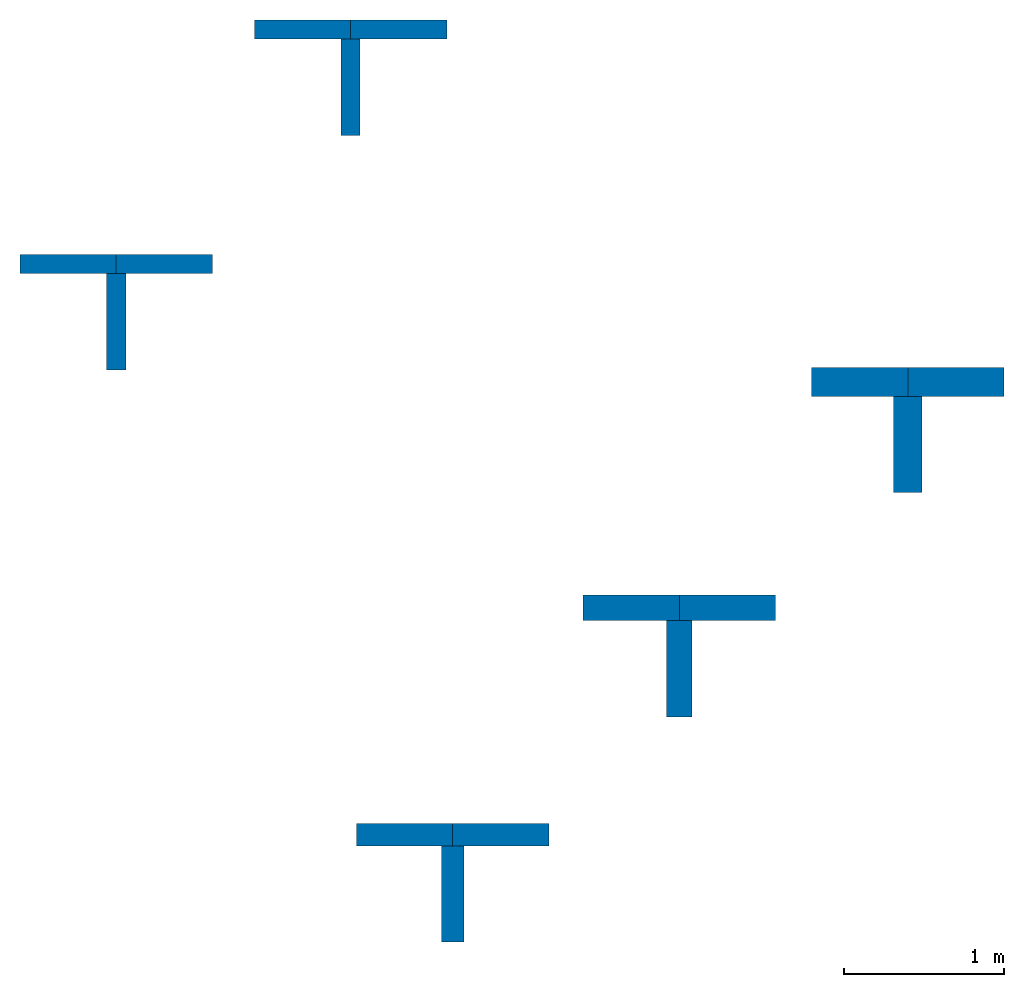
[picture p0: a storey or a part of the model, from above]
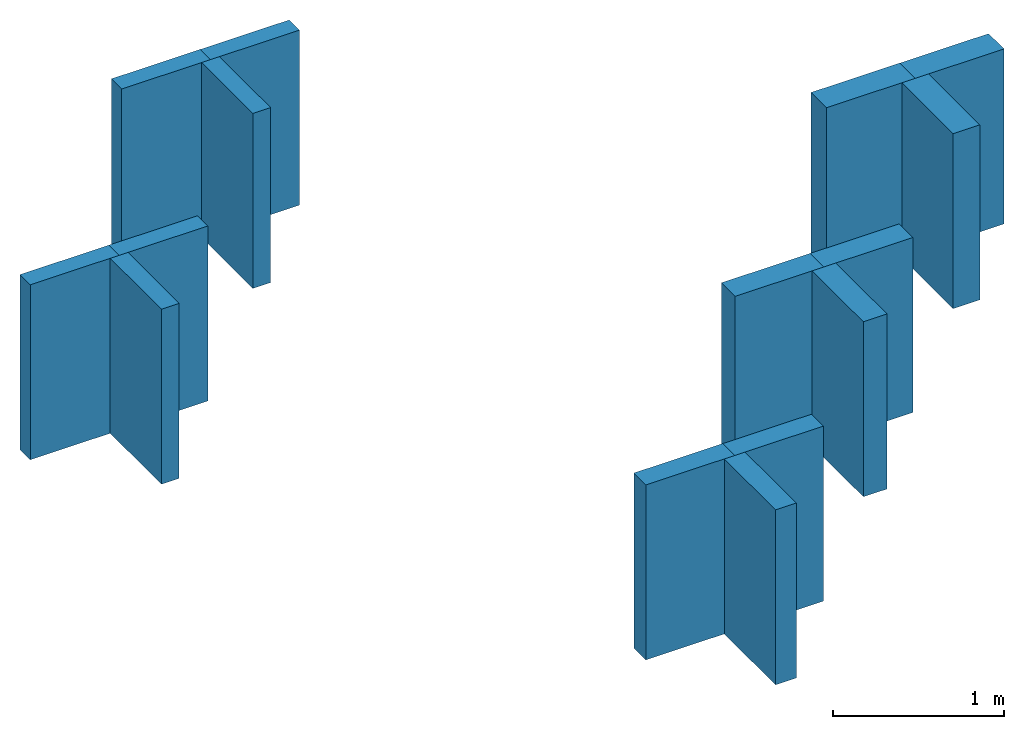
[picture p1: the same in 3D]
Properties of the parts of a building model (IFC2X3)

# File
Description: ViewDefinition [CoordinationView]
Time: 2023-01-18T13:19:16
Written by: The EXPRESS Data Manager Version 5.02.0100.07 : 28 Aug 2013
Made in: 21.1.70.21 - Exporter 21.1.70.21 - Alternate UI 21.1.70.21
Comment: STEP Physical File produced by: The EXPRESS Data Manager Version 5.02.0100.07 : 28 Aug 2013 * Module: EDMstepFileFactory/EDMstandAlone * Creation date: Wed Jan 18 13:19:16 2023 * Host: BIM-LT03 * Database: C:\Users\DONNEE~1\AppData\Local\Temp\6dfd9f73-01cb-4fe2-bb7c-203e315a706e\86299734-407f-49fc-b1f2-134ff55dd5cc\ifc * Database version: 5507 * Database creation date: Wed Jan 18 13:19:15 2023 * Schema: IFC2X3 * Model: DataRepository.ifc * Model creation date: Wed Jan 18 13:19:15 2023 * Header model: DataRepository.ifc_HeaderModel * Header model creation date: Wed Jan 18 13:19:15 2023 * EDMuser: sdai-user * EDMgroup: sdai-group * License ID and type: 5605 : Permanent license. Expiry date: * EDMstepFileFactory options: 020000

# IfcSite, Default
RefLatitude: 42, 24, 53, 508911; RefLongitude: -71, -15, -29, -58837; RefElevation: 0 mm
Pset_ProductRequirements - Category: Project Information

# IfcBuilding
Pset_BuildingCommon - NumberOfStoreys: 1
Pset_ProductRequirements - Category: Project Information

# IfcBuildingStorey: Level:NL_00_niveau, Begane grond
LongName: Begane grond; Elevation: 0 mm
Pset_AirSideSystemInformation - Name: Begane grond
Pset_ProductRequirements - Name: Begane grond; Category: Levels

# IfcWallStandardCase: Basic Wall:NLRS_21_WA_SmartCavity 031_100x600x1250mm (3)
In: Begane grond
Type - PredefinedType: STANDARD; Material: Knauf Insulation_Ecose® glaswol_TP 432KD 120 mm
Type - Pset_ElementShading - Roughness: 304.8 mm
Type - Pset_ManufacturerTypeInformation - Manufacturer: Knauf Insulation B.V.
Type - Pset_ProductRequirements - Category: Walls
Type - Pset_QuantityTakeOff - Reference: Basic Wall:NLRS_21_WA_SmartCavity 031_100x600x1250mm
Type - Pset_ReinforcementBarPitchOfWall - Description: SmartCavity 031 - 100mm; Reference: Basic Wall:NLRS_21_WA_SmartCavity 031_100x600x1250mm
Type - Pset_WallCommon - IsExternal: no; Reference: Basic Wall:NLRS_21_WA_SmartCavity 031_100x600x1250mm; ThermalTransmittance: 0.283333 kg/K/s3
Type - Pset_Wall Schedule SmartCavity031 LOD400 - Assembly Code: 21; Type Image: Raster image: SMARTCAVITY 031_Packshot_3.jpg; Model: SmartCavity 031 is een stevige met zwart glasvlies beklede glaswol spouwplaat met ECOSE® Technology; Manufacturer: Knauf Insulation B.V.; URL: www.knaufinsulation.nl www.knaufinsulation.nl www.knaufinsulation.nl; Description: SmartCavity 031 - 100mm; phone: +31(0)162-421245; email: customerservice.nl@knaufinsulation.com; product URL: https://www.knaufinsulation.nl/producten-van-knauf-insulation/SmartCavity-031; warmteweerstand: 3.2; NLRS_C_Code_Brandklasse: A1; warmtegeleidingscoëfficiënt: 0.031; kortstondige waterabsorptie: WS; langdurige waterabsorptie: WL(P); luchtstroomweerstand: AFr12; DoP nummer (Declaration of performance): G4220PPCPR; NLRS_C_content_creator: Knauf Insulation; NLRS_C_content_versie: V1.0; diktebereik: 30 - 260; diktetolerantie: T4; platen / pak: 5; pak (m2): 3.75; pakken / pallet: 20; pallet (m2): 75
Classification: 21 Buitenwanden (Uniformat)
Pset_WallCommon - IsExternal: yes; ExtendToStructure: no; LoadBearing: no
Pset_Wall Schedule SmartCavity031 LOD400 - Type: Basic Wall: NLRS_21_WA_SmartCavity 031_100x600x1250mm
Name (Basic Wall:NLRS_21_WA_SmartCavity 031_100x600x1250mm:...)
8517
8518
8519

# IfcWallStandardCase: Basic Wall:NLRS_21_WA_SmartCavity 031_120x600x1250mm (3)
In: Begane grond
Type - PredefinedType: STANDARD; Material: Knauf Insulation_Ecose® glaswol_TP 432KD 120 mm
Type - Pset_ElementShading - Roughness: 304.8 mm
Type - Pset_ManufacturerTypeInformation - Manufacturer: Knauf Insulation B.V.
Type - Pset_ProductRequirements - Category: Walls
Type - Pset_QuantityTakeOff - Reference: Basic Wall:NLRS_21_WA_SmartCavity 031_120x600x1250mm
Type - Pset_ReinforcementBarPitchOfWall - Description: SmartCavity 031 - 120mm; Reference: Basic Wall:NLRS_21_WA_SmartCavity 031_120x600x1250mm
Type - Pset_WallCommon - Reference: Basic Wall:NLRS_21_WA_SmartCavity 031_120x600x1250mm; ThermalTransmittance: 0.283333 kg/K/s3; IsExternal: no
Type - Pset_Wall Schedule SmartCavity031 LOD400 - Assembly Code: 21; Type Image: Raster image: SMARTCAVITY 031_Packshot_3.jpg; Model: SmartCavity 031 is een stevige met zwart glasvlies beklede glaswol spouwplaat met ECOSE® Technology; Manufacturer: Knauf Insulation B.V.; URL: www.knaufinsulation.nl www.knaufinsulation.nl www.knaufinsulation.nl; Description: SmartCavity 031 - 120mm; phone: +31(0)162-421245; email: customerservice.nl@knaufinsulation.com; product URL: https://www.knaufinsulation.nl/producten-van-knauf-insulation/SmartCavity-031; warmteweerstand: 3.85; NLRS_C_Code_Brandklasse: A1; warmtegeleidingscoëfficiënt: 0.031; kortstondige waterabsorptie: WS; langdurige waterabsorptie: WL(P); luchtstroomweerstand: AFr12; DoP nummer (Declaration of performance): G4220PPCPR; NLRS_C_content_creator: Knauf Insulation; NLRS_C_content_versie: V1.0; diktebereik: 30 - 260; diktetolerantie: T4; platen / pak: 4; pak (m2): 3; pakken / pallet: 20; pallet (m2): 60
Classification: 21 Buitenwanden (Uniformat)
Pset_WallCommon - IsExternal: yes; ExtendToStructure: no; LoadBearing: no
Pset_Wall Schedule SmartCavity031 LOD400 - Type: Basic Wall: NLRS_21_WA_SmartCavity 031_120x600x1250mm
Name (Basic Wall:NLRS_21_WA_SmartCavity 031_120x600x1250mm:...)
2447
2448
2449

# IfcWallStandardCase: Basic Wall:NLRS_21_WA_SmartCavity 031_140x600x1250mm (3)
In: Begane grond
Type - PredefinedType: STANDARD; Material: Knauf Insulation_Ecose® glaswol_TP 432KD 140 mm
Type - Pset_ElementShading - Roughness: 304.8 mm
Type - Pset_ManufacturerTypeInformation - Manufacturer: Knauf Insulation B.V.
Type - Pset_ProductRequirements - Category: Walls
Type - Pset_QuantityTakeOff - Reference: Basic Wall:NLRS_21_WA_SmartCavity 031_140x600x1250mm
Type - Pset_ReinforcementBarPitchOfWall - Description: SmartCavity 031 - 140mm; Reference: Basic Wall:NLRS_21_WA_SmartCavity 031_140x600x1250mm
Type - Pset_WallCommon - IsExternal: no; Reference: Basic Wall:NLRS_21_WA_SmartCavity 031_140x600x1250mm; ThermalTransmittance: 0.242857 kg/K/s3
Type - Pset_Wall Schedule SmartCavity031 LOD400 - platen / pak: 4; pak (m2): 3; Assembly Code: 21; Type Image: Raster image: SMARTCAVITY 031_Packshot_3.jpg; Model: SmartCavity 031 is een stevige met zwart glasvlies beklede glaswol spouwplaat met ECOSE® Technology; Manufacturer: Knauf Insulation B.V.; URL: www.knaufinsulation.nl www.knaufinsulation.nl www.knaufinsulation.nl; Description: SmartCavity 031 - 140mm; phone: +31(0)162-421245; email: customerservice.nl@knaufinsulation.com; product URL: https://www.knaufinsulation.nl/producten-van-knauf-insulation/SmartCavity-031; warmteweerstand: 4.5; NLRS_C_Code_Brandklasse: A1; warmtegeleidingscoëfficiënt: 0.031; kortstondige waterabsorptie: WS; langdurige waterabsorptie: WL(P); luchtstroomweerstand: AFr12; DoP nummer (Declaration of performance): G4220PPCPR; NLRS_C_content_creator: Knauf Insulation; NLRS_C_content_versie: V1.0; diktebereik: 30 - 260; diktetolerantie: T4; pakken / pallet: 16; pallet (m2): 48
Classification: 21 Buitenwanden (Uniformat)
Pset_WallCommon - IsExternal: yes; ExtendToStructure: no; LoadBearing: no
Pset_Wall Schedule SmartCavity031 LOD400 - Type: Basic Wall: NLRS_21_WA_SmartCavity 031_140x600x1250mm
Name (Basic Wall:NLRS_21_WA_SmartCavity 031_140x600x1250mm:...)
2450
2451
2452

# IfcWallStandardCase: Basic Wall:NLRS_21_WA_SmartCavity 031_160x600x1250mm (3)
In: Begane grond
Type - PredefinedType: STANDARD; Material: Knauf Insulation_Ecose® glaswol_TP 432KD 160 mm
Type - Pset_ElementShading - Roughness: 304.8 mm
Type - Pset_ManufacturerTypeInformation - Manufacturer: Knauf Insulation B.V.
Type - Pset_ProductRequirements - Category: Walls
Type - Pset_QuantityTakeOff - Reference: Basic Wall:NLRS_21_WA_SmartCavity 031_160x600x1250mm
Type - Pset_ReinforcementBarPitchOfWall - Description: SmartCavity 031 - 160mm; Reference: Basic Wall:NLRS_21_WA_SmartCavity 031_160x600x1250mm
Type - Pset_WallCommon - IsExternal: no; Reference: Basic Wall:NLRS_21_WA_SmartCavity 031_160x600x1250mm; ThermalTransmittance: 0.2125 kg/K/s3
Type - Pset_Wall Schedule SmartCavity031 LOD400 - Assembly Code: 21; Type Image: Raster image: SMARTCAVITY 031_Packshot_3.jpg; Model: SmartCavity 031 is een stevige met zwart glasvlies beklede glaswol spouwplaat met ECOSE® Technology; Manufacturer: Knauf Insulation B.V.; URL: www.knaufinsulation.nl www.knaufinsulation.nl www.knaufinsulation.nl; Description: SmartCavity 031 - 160mm; phone: +31(0)162-421245; email: customerservice.nl@knaufinsulation.com; product URL: https://www.knaufinsulation.nl/producten-van-knauf-insulation/SmartCavity-031; warmteweerstand: 5.15; NLRS_C_Code_Brandklasse: A1; warmtegeleidingscoëfficiënt: 0.031; kortstondige waterabsorptie: WS; langdurige waterabsorptie: WL(P); luchtstroomweerstand: AFr12; DoP nummer (Declaration of performance): G4220PPCPR; NLRS_C_content_creator: Knauf Insulation; NLRS_C_content_versie: V1.0; diktebereik: 30 - 260; diktetolerantie: T4; platen / pak: 3; pak (m2): 2.25; pakken / pallet: 20; pallet (m2): 45
Classification: 21 Buitenwanden (Uniformat)
Pset_WallCommon - IsExternal: yes; ExtendToStructure: no; LoadBearing: no
Pset_Wall Schedule SmartCavity031 LOD400 - Type: Basic Wall: NLRS_21_WA_SmartCavity 031_160x600x1250mm
Name (Basic Wall:NLRS_21_WA_SmartCavity 031_160x600x1250mm:...)
2453
2454
2455

# IfcWallStandardCase: Basic Wall:NLRS_21_WA_SmartCavity 031_180x600x1250mm (3)
In: Begane grond
Type - PredefinedType: STANDARD; Material: Knauf Insulation_Ecose® glaswol_TP 432KD 180 mm
Type - Pset_ElementShading - Roughness: 304.8 mm
Type - Pset_ManufacturerTypeInformation - Manufacturer: Knauf Insulation B.V.
Type - Pset_ProductRequirements - Category: Walls
Type - Pset_QuantityTakeOff - Reference: Basic Wall:NLRS_21_WA_SmartCavity 031_180x600x1250mm
Type - Pset_ReinforcementBarPitchOfWall - Description: SmartCavity 031 - 180mm; Reference: Basic Wall:NLRS_21_WA_SmartCavity 031_180x600x1250mm
Type - Pset_WallCommon - IsExternal: no; Reference: Basic Wall:NLRS_21_WA_SmartCavity 031_180x600x1250mm; ThermalTransmittance: 0.188889 kg/K/s3
Type - Pset_Wall Schedule SmartCavity031 LOD400 - platen / pak: 3; Assembly Code: 21; Type Image: Raster image: SMARTCAVITY 031_Packshot_3.jpg; Model: SmartCavity 031 is een stevige met zwart glasvlies beklede glaswol spouwplaat met ECOSE® Technology; Manufacturer: Knauf Insulation B.V.; URL: www.knaufinsulation.nl www.knaufinsulation.nl www.knaufinsulation.nl; Description: SmartCavity 031 - 180mm; phone: +31(0)162-421245; email: customerservice.nl@knaufinsulation.com; product URL: https://www.knaufinsulation.nl/producten-van-knauf-insulation/SmartCavity-031; warmteweerstand: 5.8; NLRS_C_Code_Brandklasse: A1; warmtegeleidingscoëfficiënt: 0.031; kortstondige waterabsorptie: WS; langdurige waterabsorptie: WL(P); luchtstroomweerstand: AFr12; DoP nummer (Declaration of performance): G4220PPCPR; NLRS_C_content_creator: Knauf Insulation; NLRS_C_content_versie: V1.0; diktebereik: 30 - 260; diktetolerantie: T4; pak (m2): 2.25; pakken / pallet: 16; pallet (m2): 36
Classification: 21 Buitenwanden (Uniformat)
Pset_WallCommon - IsExternal: yes; ExtendToStructure: no; LoadBearing: no
Pset_Wall Schedule SmartCavity031 LOD400 - Type: Basic Wall: NLRS_21_WA_SmartCavity 031_180x600x1250mm
Name (Basic Wall:NLRS_21_WA_SmartCavity 031_180x600x1250mm:...)
2457
2458
2459
